VERSION 5.8 ;
BUSBITCHARS "[]" ;
DIVIDERCHAR "/" ;
UNITS
  DATABASE MICRONS 1000 ;
END UNITS
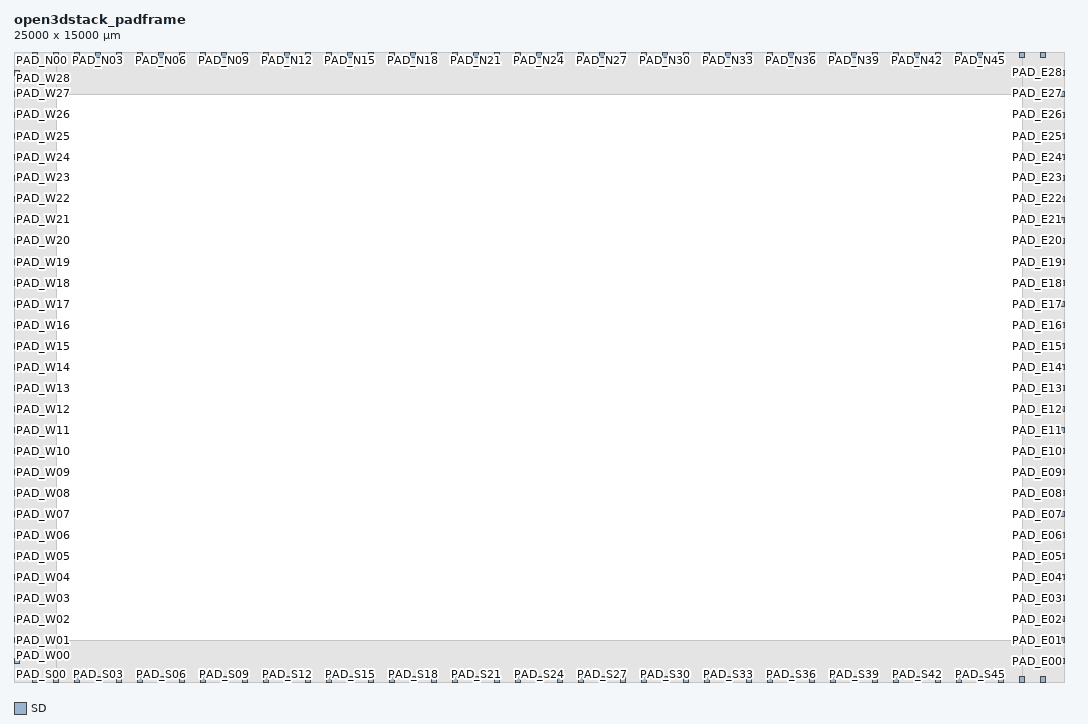
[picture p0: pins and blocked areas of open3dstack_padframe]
MACRO open3dstack_padframe
  CLASS BLOCK ;
  ORIGIN 0 0 ;
  FOREIGN open3dstack_padframe 0 0 ;
  SIZE 25000 BY 15000 ;
  SYMMETRY X Y ;
  PIN PAD_S00
    DIRECTION INOUT ;
    USE SIGNAL ;
    PORT
      LAYER SD ;
        RECT 450 0 550 130 ;
    END
  END PAD_S00
  PIN PAD_S01
    DIRECTION INOUT ;
    USE SIGNAL ;
    PORT
      LAYER SD ;
        RECT 950 0 1050 130 ;
    END
  END PAD_S01
  PIN PAD_S02
    DIRECTION INOUT ;
    USE SIGNAL ;
    PORT
      LAYER SD ;
        RECT 1450 0 1550 130 ;
    END
  END PAD_S02
  PIN PAD_S03
    DIRECTION INOUT ;
    USE SIGNAL ;
    PORT
      LAYER SD ;
        RECT 1950 0 2050 130 ;
    END
  END PAD_S03
  PIN PAD_S04
    DIRECTION INOUT ;
    USE SIGNAL ;
    PORT
      LAYER SD ;
        RECT 2450 0 2550 130 ;
    END
  END PAD_S04
  PIN PAD_S05
    DIRECTION INOUT ;
    USE SIGNAL ;
    PORT
      LAYER SD ;
        RECT 2950 0 3050 130 ;
    END
  END PAD_S05
  PIN PAD_S06
    DIRECTION INOUT ;
    USE SIGNAL ;
    PORT
      LAYER SD ;
        RECT 3450 0 3550 130 ;
    END
  END PAD_S06
  PIN PAD_S07
    DIRECTION INOUT ;
    USE SIGNAL ;
    PORT
      LAYER SD ;
        RECT 3950 0 4050 130 ;
    END
  END PAD_S07
  PIN PAD_S08
    DIRECTION INOUT ;
    USE SIGNAL ;
    PORT
      LAYER SD ;
        RECT 4450 0 4550 130 ;
    END
  END PAD_S08
  PIN PAD_S09
    DIRECTION INOUT ;
    USE SIGNAL ;
    PORT
      LAYER SD ;
        RECT 4950 0 5050 130 ;
    END
  END PAD_S09
  PIN PAD_S10
    DIRECTION INOUT ;
    USE SIGNAL ;
    PORT
      LAYER SD ;
        RECT 5450 0 5550 130 ;
    END
  END PAD_S10
  PIN PAD_S11
    DIRECTION INOUT ;
    USE SIGNAL ;
    PORT
      LAYER SD ;
        RECT 5950 0 6050 130 ;
    END
  END PAD_S11
  PIN PAD_S12
    DIRECTION INOUT ;
    USE SIGNAL ;
    PORT
      LAYER SD ;
        RECT 6450 0 6550 130 ;
    END
  END PAD_S12
  PIN PAD_S13
    DIRECTION INOUT ;
    USE SIGNAL ;
    PORT
      LAYER SD ;
        RECT 6950 0 7050 130 ;
    END
  END PAD_S13
  PIN PAD_S14
    DIRECTION INOUT ;
    USE SIGNAL ;
    PORT
      LAYER SD ;
        RECT 7450 0 7550 130 ;
    END
  END PAD_S14
  PIN PAD_S15
    DIRECTION INOUT ;
    USE SIGNAL ;
    PORT
      LAYER SD ;
        RECT 7950 0 8050 130 ;
    END
  END PAD_S15
  PIN PAD_S16
    DIRECTION INOUT ;
    USE SIGNAL ;
    PORT
      LAYER SD ;
        RECT 8450 0 8550 130 ;
    END
  END PAD_S16
  PIN PAD_S17
    DIRECTION INOUT ;
    USE SIGNAL ;
    PORT
      LAYER SD ;
        RECT 8950 0 9050 130 ;
    END
  END PAD_S17
  PIN PAD_S18
    DIRECTION INOUT ;
    USE SIGNAL ;
    PORT
      LAYER SD ;
        RECT 9450 0 9550 130 ;
    END
  END PAD_S18
  PIN PAD_S19
    DIRECTION INOUT ;
    USE SIGNAL ;
    PORT
      LAYER SD ;
        RECT 9950 0 10050 130 ;
    END
  END PAD_S19
  PIN PAD_S20
    DIRECTION INOUT ;
    USE SIGNAL ;
    PORT
      LAYER SD ;
        RECT 10450 0 10550 130 ;
    END
  END PAD_S20
  PIN PAD_S21
    DIRECTION INOUT ;
    USE SIGNAL ;
    PORT
      LAYER SD ;
        RECT 10950 0 11050 130 ;
    END
  END PAD_S21
  PIN PAD_S22
    DIRECTION INOUT ;
    USE SIGNAL ;
    PORT
      LAYER SD ;
        RECT 11450 0 11550 130 ;
    END
  END PAD_S22
  PIN PAD_S23
    DIRECTION INOUT ;
    USE SIGNAL ;
    PORT
      LAYER SD ;
        RECT 11950 0 12050 130 ;
    END
  END PAD_S23
  PIN PAD_S24
    DIRECTION INOUT ;
    USE SIGNAL ;
    PORT
      LAYER SD ;
        RECT 12450 0 12550 130 ;
    END
  END PAD_S24
  PIN PAD_S25
    DIRECTION INOUT ;
    USE SIGNAL ;
    PORT
      LAYER SD ;
        RECT 12950 0 13050 130 ;
    END
  END PAD_S25
  PIN PAD_S26
    DIRECTION INOUT ;
    USE SIGNAL ;
    PORT
      LAYER SD ;
        RECT 13450 0 13550 130 ;
    END
  END PAD_S26
  PIN PAD_S27
    DIRECTION INOUT ;
    USE SIGNAL ;
    PORT
      LAYER SD ;
        RECT 13950 0 14050 130 ;
    END
  END PAD_S27
  PIN PAD_S28
    DIRECTION INOUT ;
    USE SIGNAL ;
    PORT
      LAYER SD ;
        RECT 14450 0 14550 130 ;
    END
  END PAD_S28
  PIN PAD_S29
    DIRECTION INOUT ;
    USE SIGNAL ;
    PORT
      LAYER SD ;
        RECT 14950 0 15050 130 ;
    END
  END PAD_S29
  PIN PAD_S30
    DIRECTION INOUT ;
    USE SIGNAL ;
    PORT
      LAYER SD ;
        RECT 15450 0 15550 130 ;
    END
  END PAD_S30
  PIN PAD_S31
    DIRECTION INOUT ;
    USE SIGNAL ;
    PORT
      LAYER SD ;
        RECT 15950 0 16050 130 ;
    END
  END PAD_S31
  PIN PAD_S32
    DIRECTION INOUT ;
    USE SIGNAL ;
    PORT
      LAYER SD ;
        RECT 16450 0 16550 130 ;
    END
  END PAD_S32
  PIN PAD_S33
    DIRECTION INOUT ;
    USE SIGNAL ;
    PORT
      LAYER SD ;
        RECT 16950 0 17050 130 ;
    END
  END PAD_S33
  PIN PAD_S34
    DIRECTION INOUT ;
    USE SIGNAL ;
    PORT
      LAYER SD ;
        RECT 17450 0 17550 130 ;
    END
  END PAD_S34
  PIN PAD_S35
    DIRECTION INOUT ;
    USE SIGNAL ;
    PORT
      LAYER SD ;
        RECT 17950 0 18050 130 ;
    END
  END PAD_S35
  PIN PAD_S36
    DIRECTION INOUT ;
    USE SIGNAL ;
    PORT
      LAYER SD ;
        RECT 18450 0 18550 130 ;
    END
  END PAD_S36
  PIN PAD_S37
    DIRECTION INOUT ;
    USE SIGNAL ;
    PORT
      LAYER SD ;
        RECT 18950 0 19050 130 ;
    END
  END PAD_S37
  PIN PAD_S38
    DIRECTION INOUT ;
    USE SIGNAL ;
    PORT
      LAYER SD ;
        RECT 19450 0 19550 130 ;
    END
  END PAD_S38
  PIN PAD_S39
    DIRECTION INOUT ;
    USE SIGNAL ;
    PORT
      LAYER SD ;
        RECT 19950 0 20050 130 ;
    END
  END PAD_S39
  PIN PAD_S40
    DIRECTION INOUT ;
    USE SIGNAL ;
    PORT
      LAYER SD ;
        RECT 20450 0 20550 130 ;
    END
  END PAD_S40
  PIN PAD_S41
    DIRECTION INOUT ;
    USE SIGNAL ;
    PORT
      LAYER SD ;
        RECT 20950 0 21050 130 ;
    END
  END PAD_S41
  PIN PAD_S42
    DIRECTION INOUT ;
    USE SIGNAL ;
    PORT
      LAYER SD ;
        RECT 21450 0 21550 130 ;
    END
  END PAD_S42
  PIN PAD_S43
    DIRECTION INOUT ;
    USE SIGNAL ;
    PORT
      LAYER SD ;
        RECT 21950 0 22050 130 ;
    END
  END PAD_S43
  PIN PAD_S44
    DIRECTION INOUT ;
    USE SIGNAL ;
    PORT
      LAYER SD ;
        RECT 22450 0 22550 130 ;
    END
  END PAD_S44
  PIN PAD_S45
    DIRECTION INOUT ;
    USE SIGNAL ;
    PORT
      LAYER SD ;
        RECT 22950 0 23050 130 ;
    END
  END PAD_S45
  PIN PAD_S46
    DIRECTION INOUT ;
    USE SIGNAL ;
    PORT
      LAYER SD ;
        RECT 23450 0 23550 130 ;
    END
  END PAD_S46
  PIN PAD_S47
    DIRECTION INOUT ;
    USE SIGNAL ;
    PORT
      LAYER SD ;
        RECT 23950 0 24050 130 ;
    END
  END PAD_S47
  PIN PAD_S48
    DIRECTION INOUT ;
    USE SIGNAL ;
    PORT
      LAYER SD ;
        RECT 24450 0 24550 130 ;
    END
  END PAD_S48
  PIN PAD_E00
    DIRECTION INOUT ;
    USE SIGNAL ;
    PORT
      LAYER SD ;
        RECT 24870 450 25000 550 ;
    END
  END PAD_E00
  PIN PAD_E01
    DIRECTION INOUT ;
    USE SIGNAL ;
    PORT
      LAYER SD ;
        RECT 24870 950 25000 1050 ;
    END
  END PAD_E01
  PIN PAD_E02
    DIRECTION INOUT ;
    USE SIGNAL ;
    PORT
      LAYER SD ;
        RECT 24870 1450 25000 1550 ;
    END
  END PAD_E02
  PIN PAD_E03
    DIRECTION INOUT ;
    USE SIGNAL ;
    PORT
      LAYER SD ;
        RECT 24870 1950 25000 2050 ;
    END
  END PAD_E03
  PIN PAD_E04
    DIRECTION INOUT ;
    USE SIGNAL ;
    PORT
      LAYER SD ;
        RECT 24870 2450 25000 2550 ;
    END
  END PAD_E04
  PIN PAD_E05
    DIRECTION INOUT ;
    USE SIGNAL ;
    PORT
      LAYER SD ;
        RECT 24870 2950 25000 3050 ;
    END
  END PAD_E05
  PIN PAD_E06
    DIRECTION INOUT ;
    USE SIGNAL ;
    PORT
      LAYER SD ;
        RECT 24870 3450 25000 3550 ;
    END
  END PAD_E06
  PIN PAD_E07
    DIRECTION INOUT ;
    USE SIGNAL ;
    PORT
      LAYER SD ;
        RECT 24870 3950 25000 4050 ;
    END
  END PAD_E07
  PIN PAD_E08
    DIRECTION INOUT ;
    USE SIGNAL ;
    PORT
      LAYER SD ;
        RECT 24870 4450 25000 4550 ;
    END
  END PAD_E08
  PIN PAD_E09
    DIRECTION INOUT ;
    USE SIGNAL ;
    PORT
      LAYER SD ;
        RECT 24870 4950 25000 5050 ;
    END
  END PAD_E09
  PIN PAD_E10
    DIRECTION INOUT ;
    USE SIGNAL ;
    PORT
      LAYER SD ;
        RECT 24870 5450 25000 5550 ;
    END
  END PAD_E10
  PIN PAD_E11
    DIRECTION INOUT ;
    USE SIGNAL ;
    PORT
      LAYER SD ;
        RECT 24870 5950 25000 6050 ;
    END
  END PAD_E11
  PIN PAD_E12
    DIRECTION INOUT ;
    USE SIGNAL ;
    PORT
      LAYER SD ;
        RECT 24870 6450 25000 6550 ;
    END
  END PAD_E12
  PIN PAD_E13
    DIRECTION INOUT ;
    USE SIGNAL ;
    PORT
      LAYER SD ;
        RECT 24870 6950 25000 7050 ;
    END
  END PAD_E13
  PIN PAD_E14
    DIRECTION INOUT ;
    USE SIGNAL ;
    PORT
      LAYER SD ;
        RECT 24870 7450 25000 7550 ;
    END
  END PAD_E14
  PIN PAD_E15
    DIRECTION INOUT ;
    USE SIGNAL ;
    PORT
      LAYER SD ;
        RECT 24870 7950 25000 8050 ;
    END
  END PAD_E15
  PIN PAD_E16
    DIRECTION INOUT ;
    USE SIGNAL ;
    PORT
      LAYER SD ;
        RECT 24870 8450 25000 8550 ;
    END
  END PAD_E16
  PIN PAD_E17
    DIRECTION INOUT ;
    USE SIGNAL ;
    PORT
      LAYER SD ;
        RECT 24870 8950 25000 9050 ;
    END
  END PAD_E17
  PIN PAD_E18
    DIRECTION INOUT ;
    USE SIGNAL ;
    PORT
      LAYER SD ;
        RECT 24870 9450 25000 9550 ;
    END
  END PAD_E18
  PIN PAD_E19
    DIRECTION INOUT ;
    USE SIGNAL ;
    PORT
      LAYER SD ;
        RECT 24870 9950 25000 10050 ;
    END
  END PAD_E19
  PIN PAD_E20
    DIRECTION INOUT ;
    USE SIGNAL ;
    PORT
      LAYER SD ;
        RECT 24870 10450 25000 10550 ;
    END
  END PAD_E20
  PIN PAD_E21
    DIRECTION INOUT ;
    USE SIGNAL ;
    PORT
      LAYER SD ;
        RECT 24870 10950 25000 11050 ;
    END
  END PAD_E21
  PIN PAD_E22
    DIRECTION INOUT ;
    USE SIGNAL ;
    PORT
      LAYER SD ;
        RECT 24870 11450 25000 11550 ;
    END
  END PAD_E22
  PIN PAD_E23
    DIRECTION INOUT ;
    USE SIGNAL ;
    PORT
      LAYER SD ;
        RECT 24870 11950 25000 12050 ;
    END
  END PAD_E23
  PIN PAD_E24
    DIRECTION INOUT ;
    USE SIGNAL ;
    PORT
      LAYER SD ;
        RECT 24870 12450 25000 12550 ;
    END
  END PAD_E24
  PIN PAD_E25
    DIRECTION INOUT ;
    USE SIGNAL ;
    PORT
      LAYER SD ;
        RECT 24870 12950 25000 13050 ;
    END
  END PAD_E25
  PIN PAD_E26
    DIRECTION INOUT ;
    USE SIGNAL ;
    PORT
      LAYER SD ;
        RECT 24870 13450 25000 13550 ;
    END
  END PAD_E26
  PIN PAD_E27
    DIRECTION INOUT ;
    USE SIGNAL ;
    PORT
      LAYER SD ;
        RECT 24870 13950 25000 14050 ;
    END
  END PAD_E27
  PIN PAD_E28
    DIRECTION INOUT ;
    USE SIGNAL ;
    PORT
      LAYER SD ;
        RECT 24870 14450 25000 14550 ;
    END
  END PAD_E28
  PIN PAD_N00
    DIRECTION INOUT ;
    USE SIGNAL ;
    PORT
      LAYER SD ;
        RECT 450 14870 550 15000 ;
    END
  END PAD_N00
  PIN PAD_N01
    DIRECTION INOUT ;
    USE SIGNAL ;
    PORT
      LAYER SD ;
        RECT 950 14870 1050 15000 ;
    END
  END PAD_N01
  PIN PAD_N02
    DIRECTION INOUT ;
    USE SIGNAL ;
    PORT
      LAYER SD ;
        RECT 1450 14870 1550 15000 ;
    END
  END PAD_N02
  PIN PAD_N03
    DIRECTION INOUT ;
    USE SIGNAL ;
    PORT
      LAYER SD ;
        RECT 1950 14870 2050 15000 ;
    END
  END PAD_N03
  PIN PAD_N04
    DIRECTION INOUT ;
    USE SIGNAL ;
    PORT
      LAYER SD ;
        RECT 2450 14870 2550 15000 ;
    END
  END PAD_N04
  PIN PAD_N05
    DIRECTION INOUT ;
    USE SIGNAL ;
    PORT
      LAYER SD ;
        RECT 2950 14870 3050 15000 ;
    END
  END PAD_N05
  PIN PAD_N06
    DIRECTION INOUT ;
    USE SIGNAL ;
    PORT
      LAYER SD ;
        RECT 3450 14870 3550 15000 ;
    END
  END PAD_N06
  PIN PAD_N07
    DIRECTION INOUT ;
    USE SIGNAL ;
    PORT
      LAYER SD ;
        RECT 3950 14870 4050 15000 ;
    END
  END PAD_N07
  PIN PAD_N08
    DIRECTION INOUT ;
    USE SIGNAL ;
    PORT
      LAYER SD ;
        RECT 4450 14870 4550 15000 ;
    END
  END PAD_N08
  PIN PAD_N09
    DIRECTION INOUT ;
    USE SIGNAL ;
    PORT
      LAYER SD ;
        RECT 4950 14870 5050 15000 ;
    END
  END PAD_N09
  PIN PAD_N10
    DIRECTION INOUT ;
    USE SIGNAL ;
    PORT
      LAYER SD ;
        RECT 5450 14870 5550 15000 ;
    END
  END PAD_N10
  PIN PAD_N11
    DIRECTION INOUT ;
    USE SIGNAL ;
    PORT
      LAYER SD ;
        RECT 5950 14870 6050 15000 ;
    END
  END PAD_N11
  PIN PAD_N12
    DIRECTION INOUT ;
    USE SIGNAL ;
    PORT
      LAYER SD ;
        RECT 6450 14870 6550 15000 ;
    END
  END PAD_N12
  PIN PAD_N13
    DIRECTION INOUT ;
    USE SIGNAL ;
    PORT
      LAYER SD ;
        RECT 6950 14870 7050 15000 ;
    END
  END PAD_N13
  PIN PAD_N14
    DIRECTION INOUT ;
    USE SIGNAL ;
    PORT
      LAYER SD ;
        RECT 7450 14870 7550 15000 ;
    END
  END PAD_N14
  PIN PAD_N15
    DIRECTION INOUT ;
    USE SIGNAL ;
    PORT
      LAYER SD ;
        RECT 7950 14870 8050 15000 ;
    END
  END PAD_N15
  PIN PAD_N16
    DIRECTION INOUT ;
    USE SIGNAL ;
    PORT
      LAYER SD ;
        RECT 8450 14870 8550 15000 ;
    END
  END PAD_N16
  PIN PAD_N17
    DIRECTION INOUT ;
    USE SIGNAL ;
    PORT
      LAYER SD ;
        RECT 8950 14870 9050 15000 ;
    END
  END PAD_N17
  PIN PAD_N18
    DIRECTION INOUT ;
    USE SIGNAL ;
    PORT
      LAYER SD ;
        RECT 9450 14870 9550 15000 ;
    END
  END PAD_N18
  PIN PAD_N19
    DIRECTION INOUT ;
    USE SIGNAL ;
    PORT
      LAYER SD ;
        RECT 9950 14870 10050 15000 ;
    END
  END PAD_N19
  PIN PAD_N20
    DIRECTION INOUT ;
    USE SIGNAL ;
    PORT
      LAYER SD ;
        RECT 10450 14870 10550 15000 ;
    END
  END PAD_N20
  PIN PAD_N21
    DIRECTION INOUT ;
    USE SIGNAL ;
    PORT
      LAYER SD ;
        RECT 10950 14870 11050 15000 ;
    END
  END PAD_N21
  PIN PAD_N22
    DIRECTION INOUT ;
    USE SIGNAL ;
    PORT
      LAYER SD ;
        RECT 11450 14870 11550 15000 ;
    END
  END PAD_N22
  PIN PAD_N23
    DIRECTION INOUT ;
    USE SIGNAL ;
    PORT
      LAYER SD ;
        RECT 11950 14870 12050 15000 ;
    END
  END PAD_N23
  PIN PAD_N24
    DIRECTION INOUT ;
    USE SIGNAL ;
    PORT
      LAYER SD ;
        RECT 12450 14870 12550 15000 ;
    END
  END PAD_N24
  PIN PAD_N25
    DIRECTION INOUT ;
    USE SIGNAL ;
    PORT
      LAYER SD ;
        RECT 12950 14870 13050 15000 ;
    END
  END PAD_N25
  PIN PAD_N26
    DIRECTION INOUT ;
    USE SIGNAL ;
    PORT
      LAYER SD ;
        RECT 13450 14870 13550 15000 ;
    END
  END PAD_N26
  PIN PAD_N27
    DIRECTION INOUT ;
    USE SIGNAL ;
    PORT
      LAYER SD ;
        RECT 13950 14870 14050 15000 ;
    END
  END PAD_N27
  PIN PAD_N28
    DIRECTION INOUT ;
    USE SIGNAL ;
    PORT
      LAYER SD ;
        RECT 14450 14870 14550 15000 ;
    END
  END PAD_N28
  PIN PAD_N29
    DIRECTION INOUT ;
    USE SIGNAL ;
    PORT
      LAYER SD ;
        RECT 14950 14870 15050 15000 ;
    END
  END PAD_N29
  PIN PAD_N30
    DIRECTION INOUT ;
    USE SIGNAL ;
    PORT
      LAYER SD ;
        RECT 15450 14870 15550 15000 ;
    END
  END PAD_N30
  PIN PAD_N31
    DIRECTION INOUT ;
    USE SIGNAL ;
    PORT
      LAYER SD ;
        RECT 15950 14870 16050 15000 ;
    END
  END PAD_N31
  PIN PAD_N32
    DIRECTION INOUT ;
    USE SIGNAL ;
    PORT
      LAYER SD ;
        RECT 16450 14870 16550 15000 ;
    END
  END PAD_N32
  PIN PAD_N33
    DIRECTION INOUT ;
    USE SIGNAL ;
    PORT
      LAYER SD ;
        RECT 16950 14870 17050 15000 ;
    END
  END PAD_N33
  PIN PAD_N34
    DIRECTION INOUT ;
    USE SIGNAL ;
    PORT
      LAYER SD ;
        RECT 17450 14870 17550 15000 ;
    END
  END PAD_N34
  PIN PAD_N35
    DIRECTION INOUT ;
    USE SIGNAL ;
    PORT
      LAYER SD ;
        RECT 17950 14870 18050 15000 ;
    END
  END PAD_N35
  PIN PAD_N36
    DIRECTION INOUT ;
    USE SIGNAL ;
    PORT
      LAYER SD ;
        RECT 18450 14870 18550 15000 ;
    END
  END PAD_N36
  PIN PAD_N37
    DIRECTION INOUT ;
    USE SIGNAL ;
    PORT
      LAYER SD ;
        RECT 18950 14870 19050 15000 ;
    END
  END PAD_N37
  PIN PAD_N38
    DIRECTION INOUT ;
    USE SIGNAL ;
    PORT
      LAYER SD ;
        RECT 19450 14870 19550 15000 ;
    END
  END PAD_N38
  PIN PAD_N39
    DIRECTION INOUT ;
    USE SIGNAL ;
    PORT
      LAYER SD ;
        RECT 19950 14870 20050 15000 ;
    END
  END PAD_N39
  PIN PAD_N40
    DIRECTION INOUT ;
    USE SIGNAL ;
    PORT
      LAYER SD ;
        RECT 20450 14870 20550 15000 ;
    END
  END PAD_N40
  PIN PAD_N41
    DIRECTION INOUT ;
    USE SIGNAL ;
    PORT
      LAYER SD ;
        RECT 20950 14870 21050 15000 ;
    END
  END PAD_N41
  PIN PAD_N42
    DIRECTION INOUT ;
    USE SIGNAL ;
    PORT
      LAYER SD ;
        RECT 21450 14870 21550 15000 ;
    END
  END PAD_N42
  PIN PAD_N43
    DIRECTION INOUT ;
    USE SIGNAL ;
    PORT
      LAYER SD ;
        RECT 21950 14870 22050 15000 ;
    END
  END PAD_N43
  PIN PAD_N44
    DIRECTION INOUT ;
    USE SIGNAL ;
    PORT
      LAYER SD ;
        RECT 22450 14870 22550 15000 ;
    END
  END PAD_N44
  PIN PAD_N45
    DIRECTION INOUT ;
    USE SIGNAL ;
    PORT
      LAYER SD ;
        RECT 22950 14870 23050 15000 ;
    END
  END PAD_N45
  PIN PAD_N46
    DIRECTION INOUT ;
    USE SIGNAL ;
    PORT
      LAYER SD ;
        RECT 23450 14870 23550 15000 ;
    END
  END PAD_N46
  PIN PAD_N47
    DIRECTION INOUT ;
    USE SIGNAL ;
    PORT
      LAYER SD ;
        RECT 23950 14870 24050 15000 ;
    END
  END PAD_N47
  PIN PAD_N48
    DIRECTION INOUT ;
    USE SIGNAL ;
    PORT
      LAYER SD ;
        RECT 24450 14870 24550 15000 ;
    END
  END PAD_N48
  PIN PAD_W00
    DIRECTION INOUT ;
    USE SIGNAL ;
    PORT
      LAYER SD ;
        RECT 0 450 130 550 ;
    END
  END PAD_W00
  PIN PAD_W01
    DIRECTION INOUT ;
    USE SIGNAL ;
    PORT
      LAYER SD ;
        RECT 0 950 130 1050 ;
    END
  END PAD_W01
  PIN PAD_W02
    DIRECTION INOUT ;
    USE SIGNAL ;
    PORT
      LAYER SD ;
        RECT 0 1450 130 1550 ;
    END
  END PAD_W02
  PIN PAD_W03
    DIRECTION INOUT ;
    USE SIGNAL ;
    PORT
      LAYER SD ;
        RECT 0 1950 130 2050 ;
    END
  END PAD_W03
  PIN PAD_W04
    DIRECTION INOUT ;
    USE SIGNAL ;
    PORT
      LAYER SD ;
        RECT 0 2450 130 2550 ;
    END
  END PAD_W04
  PIN PAD_W05
    DIRECTION INOUT ;
    USE SIGNAL ;
    PORT
      LAYER SD ;
        RECT 0 2950 130 3050 ;
    END
  END PAD_W05
  PIN PAD_W06
    DIRECTION INOUT ;
    USE SIGNAL ;
    PORT
      LAYER SD ;
        RECT 0 3450 130 3550 ;
    END
  END PAD_W06
  PIN PAD_W07
    DIRECTION INOUT ;
    USE SIGNAL ;
    PORT
      LAYER SD ;
        RECT 0 3950 130 4050 ;
    END
  END PAD_W07
  PIN PAD_W08
    DIRECTION INOUT ;
    USE SIGNAL ;
    PORT
      LAYER SD ;
        RECT 0 4450 130 4550 ;
    END
  END PAD_W08
  PIN PAD_W09
    DIRECTION INOUT ;
    USE SIGNAL ;
    PORT
      LAYER SD ;
        RECT 0 4950 130 5050 ;
    END
  END PAD_W09
  PIN PAD_W10
    DIRECTION INOUT ;
    USE SIGNAL ;
    PORT
      LAYER SD ;
        RECT 0 5450 130 5550 ;
    END
  END PAD_W10
  PIN PAD_W11
    DIRECTION INOUT ;
    USE SIGNAL ;
    PORT
      LAYER SD ;
        RECT 0 5950 130 6050 ;
    END
  END PAD_W11
  PIN PAD_W12
    DIRECTION INOUT ;
    USE SIGNAL ;
    PORT
      LAYER SD ;
        RECT 0 6450 130 6550 ;
    END
  END PAD_W12
  PIN PAD_W13
    DIRECTION INOUT ;
    USE SIGNAL ;
    PORT
      LAYER SD ;
        RECT 0 6950 130 7050 ;
    END
  END PAD_W13
  PIN PAD_W14
    DIRECTION INOUT ;
    USE SIGNAL ;
    PORT
      LAYER SD ;
        RECT 0 7450 130 7550 ;
    END
  END PAD_W14
  PIN PAD_W15
    DIRECTION INOUT ;
    USE SIGNAL ;
    PORT
      LAYER SD ;
        RECT 0 7950 130 8050 ;
    END
  END PAD_W15
  PIN PAD_W16
    DIRECTION INOUT ;
    USE SIGNAL ;
    PORT
      LAYER SD ;
        RECT 0 8450 130 8550 ;
    END
  END PAD_W16
  PIN PAD_W17
    DIRECTION INOUT ;
    USE SIGNAL ;
    PORT
      LAYER SD ;
        RECT 0 8950 130 9050 ;
    END
  END PAD_W17
  PIN PAD_W18
    DIRECTION INOUT ;
    USE SIGNAL ;
    PORT
      LAYER SD ;
        RECT 0 9450 130 9550 ;
    END
  END PAD_W18
  PIN PAD_W19
    DIRECTION INOUT ;
    USE SIGNAL ;
    PORT
      LAYER SD ;
        RECT 0 9950 130 10050 ;
    END
  END PAD_W19
  PIN PAD_W20
    DIRECTION INOUT ;
    USE SIGNAL ;
    PORT
      LAYER SD ;
        RECT 0 10450 130 10550 ;
    END
  END PAD_W20
  PIN PAD_W21
    DIRECTION INOUT ;
    USE SIGNAL ;
    PORT
      LAYER SD ;
        RECT 0 10950 130 11050 ;
    END
  END PAD_W21
  PIN PAD_W22
    DIRECTION INOUT ;
    USE SIGNAL ;
    PORT
      LAYER SD ;
        RECT 0 11450 130 11550 ;
    END
  END PAD_W22
  PIN PAD_W23
    DIRECTION INOUT ;
    USE SIGNAL ;
    PORT
      LAYER SD ;
        RECT 0 11950 130 12050 ;
    END
  END PAD_W23
  PIN PAD_W24
    DIRECTION INOUT ;
    USE SIGNAL ;
    PORT
      LAYER SD ;
        RECT 0 12450 130 12550 ;
    END
  END PAD_W24
  PIN PAD_W25
    DIRECTION INOUT ;
    USE SIGNAL ;
    PORT
      LAYER SD ;
        RECT 0 12950 130 13050 ;
    END
  END PAD_W25
  PIN PAD_W26
    DIRECTION INOUT ;
    USE SIGNAL ;
    PORT
      LAYER SD ;
        RECT 0 13450 130 13550 ;
    END
  END PAD_W26
  PIN PAD_W27
    DIRECTION INOUT ;
    USE SIGNAL ;
    PORT
      LAYER SD ;
        RECT 0 13950 130 14050 ;
    END
  END PAD_W27
  PIN PAD_W28
    DIRECTION INOUT ;
    USE SIGNAL ;
    PORT
      LAYER SD ;
        RECT 0 14450 130 14550 ;
    END
  END PAD_W28
  OBS
    LAYER SD ;
      RECT 0 0 25000 1000 ;
      RECT 0 14000 25000 15000 ;
      RECT 0 0 1000 15000 ;
      RECT 24000 0 25000 15000 ;
  END
END open3dstack_padframe
END LIBRARY
